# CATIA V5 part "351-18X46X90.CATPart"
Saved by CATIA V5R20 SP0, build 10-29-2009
Part number: 351-18X46X90
Definition: NONE
Nomenclature: 351-18X46X90
Source: Unknown
Description: 351-18X46X90
Bounding box of the stored display mesh (mm): x -5 to 85, y -15 to 15, z -15 to 15
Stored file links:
  C:\Users\Utente\Desktop\IO LAVORO\3D X SITO CF\X SITO\PLASTICA\351\351-18X46X90.CATPart

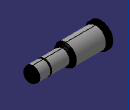
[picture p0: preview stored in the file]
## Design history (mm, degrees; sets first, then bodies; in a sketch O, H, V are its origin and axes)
Body1 "351-18X46X90" (main body)
  Solid1: solid without history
